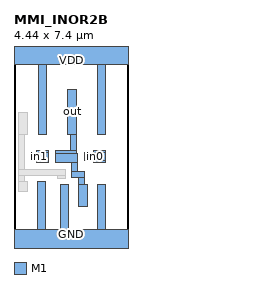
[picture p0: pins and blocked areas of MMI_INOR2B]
MACRO MMI_INOR2B
	CLASS CORE ;
	FOREIGN MMI_INOR2B 0 0 ;
	SIZE 4.44 BY 7.4 ;
	SYMMETRY X Y ;
	SITE CORE1 ;
	PIN out
		DIRECTION output ;
		USE SIGNAL ;
		PORT
			LAYER M1 ;
			RECT 2.09 4.19 2.43 5.95 ;
			LAYER M1 ;
			RECT 2.2 3.555 2.43 4.19 ;
			LAYER M1 ;
			RECT 1.625 3.445 2.43 3.555 ;
			LAYER M1 ;
			RECT 1.625 3.105 2.475 3.445 ;
			LAYER M1 ;
			RECT 2.245 2.755 2.475 3.105 ;
			LAYER M1 ;
			RECT 2.245 2.525 2.75 2.755 ;
			LAYER M1 ;
			RECT 2.52 2.24 2.75 2.525 ;
			LAYER M1 ;
			RECT 2.52 1.4 2.86 2.24 ;
		END
		AntennaDiffArea 1.4904 ;
	END out
	PIN in1
		DIRECTION input ;
		USE SIGNAL ;
		PORT
			LAYER M1 ;
			RECT 0.885 3.5 1.335 3.555 ;
			LAYER M1 ;
			RECT 0.64 3.16 1.335 3.5 ;
			LAYER M1 ;
			RECT 0.885 3.105 1.335 3.16 ;
		END
		AntennaGateArea 0.2484 ;
	END in1
	PIN GND
		DIRECTION inout ;
		USE GROUND ;
		PORT
			LAYER M1 ;
			RECT 0.9 0.5 1.24 2.35 ;
			LAYER M1 ;
			RECT 1.8 0.5 2.14 2.24 ;
			LAYER M1 ;
			RECT 3.24 0.5 3.58 2.24 ;
			LAYER M1 ;
			RECT 0 -0.5 4.44 0.5 ;
		END
	END GND
	PIN VDD
		DIRECTION inout ;
		USE POWER ;
		PORT
			LAYER M1 ;
			RECT 0 6.9 4.44 7.9 ;
			LAYER M1 ;
			RECT 0.94 4.19 1.28 6.9 ;
			LAYER M1 ;
			RECT 3.24 4.19 3.58 6.9 ;
		END
	END VDD
	PIN in0
		DIRECTION input ;
		USE SIGNAL ;
		PORT
			LAYER M1 ;
			RECT 3.105 3.5 3.555 3.555 ;
			LAYER M1 ;
			RECT 2.76 3.16 3.555 3.5 ;
			LAYER M1 ;
			RECT 3.105 3.105 3.555 3.16 ;
		END
		AntennaGateArea 0.828 ;
	END in0
	OBS
		LAYER M1 ;
		RECT 0.18 4.19 0.52 5.03 ;
		LAYER M1 ;
		RECT 0.18 2.815 0.41 4.19 ;
		LAYER M1 ;
		RECT 0.18 2.585 2.015 2.815 ;
		LAYER M1 ;
		RECT 0.18 2.35 0.41 2.585 ;
		LAYER M1 ;
		RECT 1.675 2.47 2.015 2.585 ;
		LAYER M1 ;
		RECT 0.18 1.97 0.52 2.35 ;
	END
END MMI_INOR2B
